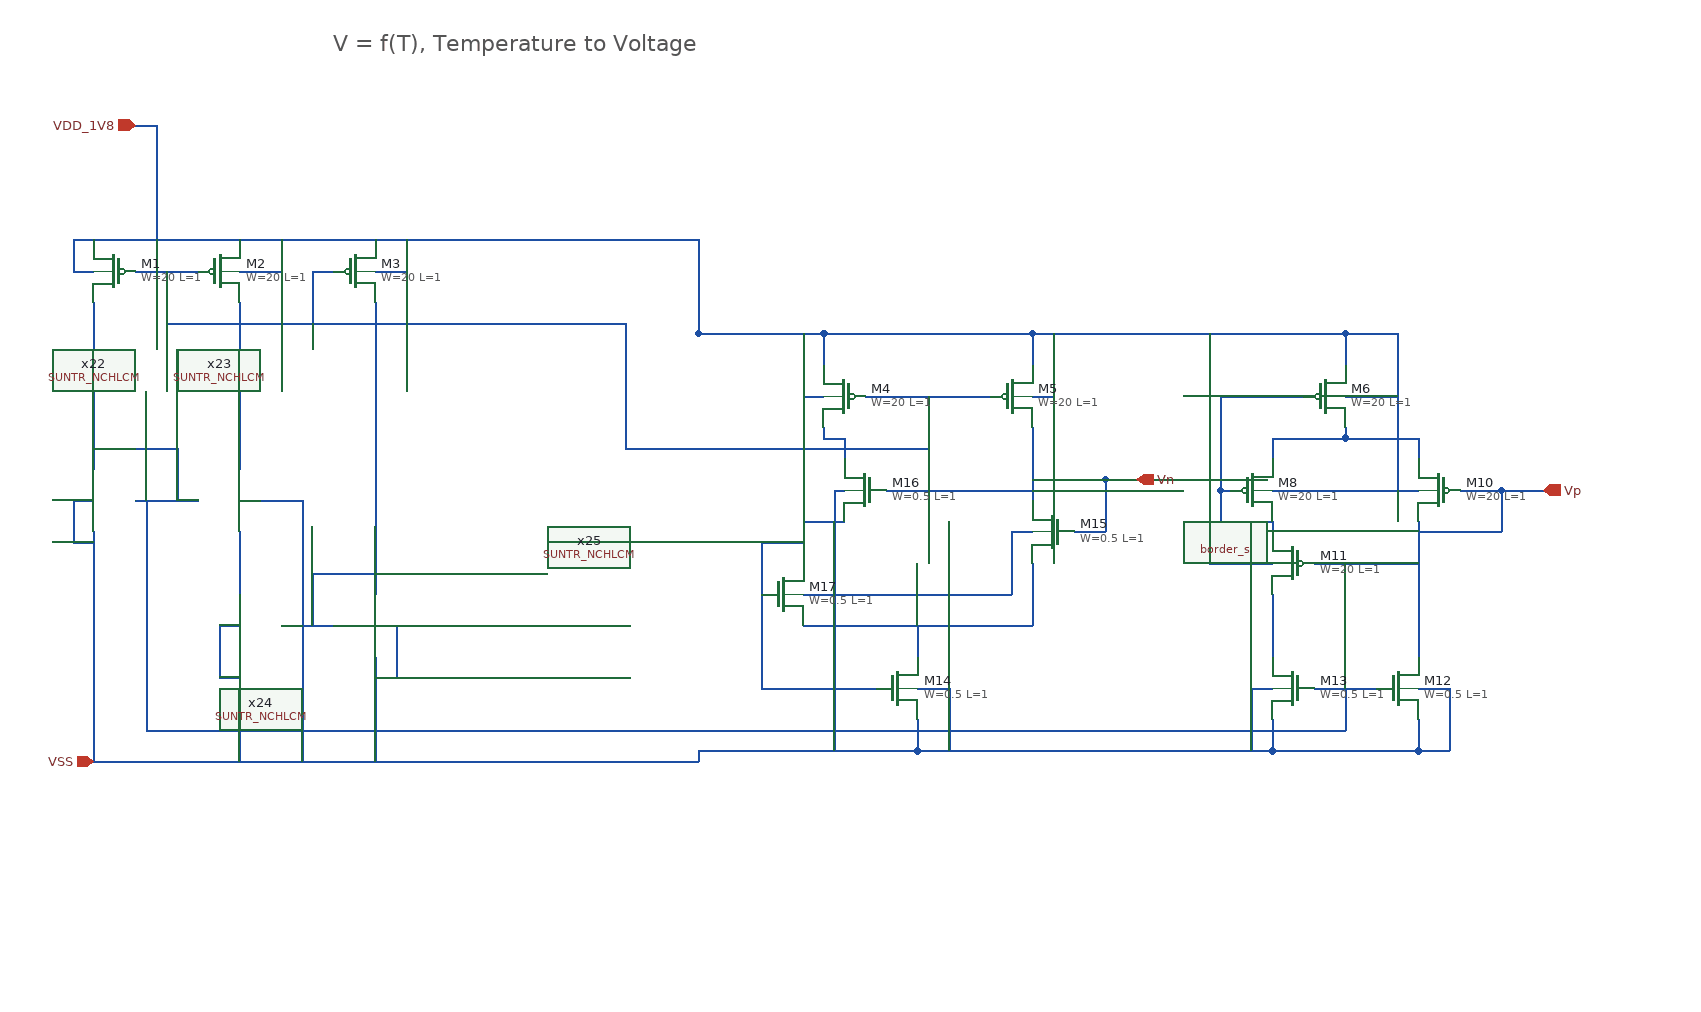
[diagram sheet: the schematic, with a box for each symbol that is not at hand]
v {xschem version=3.4.4 file_version=1.2
}
G {}
K {}
V {}
S {}
E {}
T {V = f(T), Temperature to Voltage} 400 -1040 0 0 1 1 {}
N 1070 -660 1070 -590 {
lab=Vn}
N 870 -750 870 -720 {
lab=VDD_1V8}
N 750 -750 870 -750 {
lab=VDD_1V8}
N 750 -750 870 -750 {
lab=VDD_1V8}
N 870 -750 1070 -750 {
lab=VDD_1V8}
N 1070 -750 1070 -720 {
lab=VDD_1V8}
N 1070 -610 1140 -610 {
lab=Vn}
N 1140 -610 1140 -560 {
lab=Vn}
N 1110 -560 1140 -560 {
lab=Vn}
N 1140 -610 1170 -610 {
lab=Vn}
N 1440 -570 1440 -440 {
lab=Vp}
N 1440 -650 1440 -630 {
lab=#net1}
N 1370 -650 1440 -650 {
lab=#net1}
N 1370 -660 1370 -650 {
lab=#net1}
N 1300 -650 1370 -650 {
lab=#net1}
N 1300 -650 1300 -630 {
lab=#net1}
N 1300 -570 1300 -560 {
lab=#net2}
N 1340 -530 1440 -530 {
lab=Vp}
N 1340 -410 1400 -410 {
lab=#net3}
N 1370 -750 1370 -720 {
lab=VDD_1V8}
N 1070 -750 1370 -750 {
lab=VDD_1V8}
N 1250 -690 1330 -690 {
lab=#net2}
N 1250 -690 1250 -600 {
lab=#net2}
N 1250 -600 1260 -600 {
lab=#net2}
N 1250 -600 1250 -570 {
lab=#net2}
N 1250 -570 1300 -570 {
lab=#net2}
N 1480 -600 1520 -600 {
lab=Vp}
N 1520 -600 1520 -560 {
lab=Vp}
N 1440 -560 1520 -560 {
lab=Vp}
N 1520 -600 1560 -600 {
lab=Vp}
N 1440 -380 1440 -350 {
lab=VSS}
N 1300 -350 1440 -350 {
lab=VSS}
N 1300 -380 1300 -350 {
lab=VSS}
N 960 -350 1300 -350 {
lab=VSS}
N 960 -380 960 -350 {
lab=VSS}
N 750 -350 960 -350 {
lab=VSS}
N 970 -690 970 -640 {
lab=#net4}
N 910 -690 1030 -690 {
lab=#net4}
N 1300 -500 1300 -440 {
lab=#net5}
N 890 -650 890 -630 {
lab=#net6}
N 870 -650 890 -650 {
lab=#net6}
N 870 -660 870 -650 {
lab=#net6}
N 930 -600 1070 -600 {
lab=Vn}
N 850 -690 870 -690 {
lab=VDD_1V8}
N 850 -750 850 -690 {
lab=VDD_1V8}
N 1070 -690 1090 -690 {
lab=VDD_1V8}
N 1090 -750 1090 -690 {
lab=VDD_1V8}
N 1240 -530 1300 -530 {
lab=VDD_1V8}
N 1240 -750 1240 -530 {
lab=VDD_1V8}
N 1300 -600 1440 -600 {
lab=VDD_1V8}
N 1420 -750 1420 -600 {
lab=VDD_1V8}
N 1370 -750 1420 -750 {
lab=VDD_1V8}
N 1370 -690 1420 -690 {
lab=VDD_1V8}
N 880 -600 890 -600 {
lab=VSS}
N 880 -600 880 -350 {
lab=VSS}
N 850 -470 1070 -470 {
lab=#net7}
N 960 -470 960 -440 {
lab=#net7}
N 850 -570 890 -570 {
lab=#net8}
N 850 -570 850 -530 {
lab=#net8}
N 810 -550 810 -500 {
lab=#net8}
N 810 -550 850 -550 {
lab=#net8}
N 810 -500 810 -410 {
lab=#net8}
N 810 -410 920 -410 {
lab=#net8}
N 850 -500 880 -500 {
lab=VSS}
N 1050 -560 1070 -560 {
lab=VSS}
N 1050 -560 1050 -500 {
lab=VSS}
N 880 -500 1050 -500 {
lab=VSS}
N 960 -410 990 -410 {
lab=VSS}
N 990 -410 990 -350 {
lab=VSS}
N 1280 -410 1300 -410 {
lab=VSS}
N 1280 -410 1280 -350 {
lab=VSS}
N 1440 -410 1470 -410 {
lab=VSS}
N 1470 -410 1470 -350 {
lab=VSS}
N 1440 -350 1470 -350 {
lab=VSS}
N 210 -810 270 -810 {
lab=#net4}
N 380 -810 400 -810 {
lab=#net4}
N 210 -590 270 -590 {
lab=#net3}
N 250 -630 250 -590 {
lab=#net3}
N 170 -640 250 -640 {
lab=#net3}
N 250 -640 250 -630 {
lab=#net3}
N 170 -560 170 -340 {
lab=VSS}
N 170 -340 570 -340 {
lab=VSS}
N 310 -560 310 -500 {
lab=#net9}
N 350 -470 400 -470 {
lab=#net10}
N 310 -440 310 -340 {
lab=VSS}
N 310 -840 330 -840 {
lab=VDD_1V8}
N 170 -840 310 -840 {
lab=VDD_1V8}
N 330 -840 440 -840 {
lab=VDD_1V8}
N 440 -840 560 -840 {
lab=VDD_1V8}
N 560 -840 750 -840 {
lab=VDD_1V8}
N 750 -840 750 -750 {
lab=VDD_1V8}
N 570 -340 750 -340 {
lab=VSS}
N 750 -350 750 -340 {
lab=VSS}
N 1370 -410 1370 -370 {
lab=#net3}
N 220 -370 1370 -370 {
lab=#net3}
N 220 -590 220 -370 {
lab=#net3}
N 310 -590 370 -590 {
lab=VSS}
N 370 -590 370 -340 {
lab=VSS}
N 310 -810 350 -810 {
lab=VDD_1V8}
N 350 -840 350 -810 {
lab=VDD_1V8}
N 440 -810 470 -810 {
lab=VDD_1V8}
N 470 -840 470 -810 {
lab=VDD_1V8}
N 440 -440 440 -340 {
lab=VSS}
N 380 -520 380 -470 {
lab=#net10}
N 380 -520 440 -520 {
lab=#net10}
N 150 -840 170 -840 {
lab=VDD_1V8}
N 150 -810 170 -810 {
lab=VDD_1V8}
N 150 -590 170 -590 {
lab=VSS}
N 150 -590 150 -550 {
lab=VSS}
N 150 -550 170 -550 {
lab=VSS}
N 230 -950 230 -840 {
lab=VDD_1V8}
N 210 -950 230 -950 {
lab=VDD_1V8}
N 170 -780 170 -620 {
lab=#net3}
N 310 -780 310 -620 {
lab=#net11}
N 440 -780 440 -500 {
lab=#net10}
N 240 -810 240 -760 {
lab=#net4}
N 240 -760 680 -760 {
lab=#net4}
N 680 -760 680 -640 {
lab=#net4}
N 680 -640 970 -640 {
lab=#net4}
N 380 -810 380 -760 {
lab=#net4}
N 150 -840 150 -810 {
lab=VDD_1V8}
N 290 -470 310 -470 {
lab=VSS}
N 290 -470 290 -420 {
lab=VSS}
N 290 -420 310 -420 {
lab=VSS}
N 440 -470 460 -470 {
lab=VSS}
N 460 -470 460 -420 {
lab=VSS}
N 440 -420 460 -420 {
lab=VSS}
N 1070 -530 1070 -470 {
lab=#net7}
C {cborder/border_s.sym} 1250 -170 0 0 {
user="GR06"
company="GR06"}
C {devices/ipin.sym} 210 -950 0 0 {name=p1 lab=VDD_1V8
}
C {devices/ipin.sym} 170 -340 0 0 {name=p3 lab=VSS}
C {devices/opin.sym} 1170 -610 0 0 {name=p4 lab=Vn}
C {devices/opin.sym} 1560 -600 0 0 {name=p5 lab=Vp}
C {SUN_TR_SKY130NM/SUNTR_NCHLCM.sym} 210 -590 0 1 {name=x22 }
C {SUN_TR_SKY130NM/SUNTR_NCHLCM.sym} 270 -590 0 0 {name=x23 }
C {SUN_TR_SKY130NM/SUNTR_NCHLCM.sym} 350 -470 0 1 {name=x24 }
C {SUN_TR_SKY130NM/SUNTR_NCHLCM.sym} 400 -470 0 0 {name=x25 }
C {sky130_fd_pr/pfet_01v8.sym} 190 -810 0 1 {name=M1
L=1
W=20
nf=1
mult=1
ad="'int((nf+1)/2) * W/nf * 0.29'"
pd="'2*int((nf+1)/2) * (W/nf + 0.29)'"
as="'int((nf+2)/2) * W/nf * 0.29'"
ps="'2*int((nf+2)/2) * (W/nf + 0.29)'"
nrd="'0.29 / W'" nrs="'0.29 / W'"
sa=0 sb=0 sd=0
model=pfet_01v8
spiceprefix=X
}
C {sky130_fd_pr/pfet_01v8.sym} 290 -810 0 0 {name=M2
L=1
W=20
nf=1
mult=1
ad="'int((nf+1)/2) * W/nf * 0.29'"
pd="'2*int((nf+1)/2) * (W/nf + 0.29)'"
as="'int((nf+2)/2) * W/nf * 0.29'"
ps="'2*int((nf+2)/2) * (W/nf + 0.29)'"
nrd="'0.29 / W'" nrs="'0.29 / W'"
sa=0 sb=0 sd=0
model=pfet_01v8
spiceprefix=X
}
C {sky130_fd_pr/pfet_01v8.sym} 420 -810 0 0 {name=M3
L=1
W=20
nf=1
mult=1
ad="'int((nf+1)/2) * W/nf * 0.29'"
pd="'2*int((nf+1)/2) * (W/nf + 0.29)'"
as="'int((nf+2)/2) * W/nf * 0.29'"
ps="'2*int((nf+2)/2) * (W/nf + 0.29)'"
nrd="'0.29 / W'" nrs="'0.29 / W'"
sa=0 sb=0 sd=0
model=pfet_01v8
spiceprefix=X
}
C {sky130_fd_pr/pfet_01v8.sym} 890 -690 0 1 {name=M4
L=1
W=20
nf=1
mult=1
ad="'int((nf+1)/2) * W/nf * 0.29'"
pd="'2*int((nf+1)/2) * (W/nf + 0.29)'"
as="'int((nf+2)/2) * W/nf * 0.29'"
ps="'2*int((nf+2)/2) * (W/nf + 0.29)'"
nrd="'0.29 / W'" nrs="'0.29 / W'"
sa=0 sb=0 sd=0
model=pfet_01v8
spiceprefix=X
}
C {sky130_fd_pr/pfet_01v8.sym} 1050 -690 0 0 {name=M5
L=1
W=20
nf=1
mult=1
ad="'int((nf+1)/2) * W/nf * 0.29'"
pd="'2*int((nf+1)/2) * (W/nf + 0.29)'"
as="'int((nf+2)/2) * W/nf * 0.29'"
ps="'2*int((nf+2)/2) * (W/nf + 0.29)'"
nrd="'0.29 / W'" nrs="'0.29 / W'"
sa=0 sb=0 sd=0
model=pfet_01v8
spiceprefix=X
}
C {sky130_fd_pr/pfet_01v8.sym} 1350 -690 0 0 {name=M6
L=1
W=20
nf=1
mult=1
ad="'int((nf+1)/2) * W/nf * 0.29'"
pd="'2*int((nf+1)/2) * (W/nf + 0.29)'"
as="'int((nf+2)/2) * W/nf * 0.29'"
ps="'2*int((nf+2)/2) * (W/nf + 0.29)'"
nrd="'0.29 / W'" nrs="'0.29 / W'"
sa=0 sb=0 sd=0
model=pfet_01v8
spiceprefix=X
}
C {sky130_fd_pr/pfet_01v8.sym} 1280 -600 0 0 {name=M8
L=1
W=20
nf=1
mult=1
ad="'int((nf+1)/2) * W/nf * 0.29'"
pd="'2*int((nf+1)/2) * (W/nf + 0.29)'"
as="'int((nf+2)/2) * W/nf * 0.29'"
ps="'2*int((nf+2)/2) * (W/nf + 0.29)'"
nrd="'0.29 / W'" nrs="'0.29 / W'"
sa=0 sb=0 sd=0
model=pfet_01v8
spiceprefix=X
}
C {sky130_fd_pr/pfet_01v8.sym} 1460 -600 0 1 {name=M10
L=1
W=20
nf=1
mult=1
ad="'int((nf+1)/2) * W/nf * 0.29'"
pd="'2*int((nf+1)/2) * (W/nf + 0.29)'"
as="'int((nf+2)/2) * W/nf * 0.29'"
ps="'2*int((nf+2)/2) * (W/nf + 0.29)'"
nrd="'0.29 / W'" nrs="'0.29 / W'"
sa=0 sb=0 sd=0
model=pfet_01v8
spiceprefix=X
}
C {sky130_fd_pr/pfet_01v8.sym} 1320 -530 0 1 {name=M11
L=1
W=20
nf=1
mult=1
ad="'int((nf+1)/2) * W/nf * 0.29'"
pd="'2*int((nf+1)/2) * (W/nf + 0.29)'"
as="'int((nf+2)/2) * W/nf * 0.29'"
ps="'2*int((nf+2)/2) * (W/nf + 0.29)'"
nrd="'0.29 / W'" nrs="'0.29 / W'"
sa=0 sb=0 sd=0
model=pfet_01v8
spiceprefix=X
}
C {sky130_fd_pr/nfet_01v8.sym} 1420 -410 2 1 {name=M12
L=1
W=0.5
nf=1
mult=1
ad="'int((nf+1)/2) * W/nf * 0.29'"
pd="'2*int((nf+1)/2) * (W/nf + 0.29)'"
as="'int((nf+2)/2) * W/nf * 0.29'"
ps="'2*int((nf+2)/2) * (W/nf + 0.29)'"
nrd="'0.29 / W'" nrs="'0.29 / W'"
sa=0 sb=0 sd=0
model=nfet_01v8
spiceprefix=X
}
C {sky130_fd_pr/nfet_01v8.sym} 1320 -410 2 0 {name=M13
L=1
W=0.5
nf=1
mult=1
ad="'int((nf+1)/2) * W/nf * 0.29'"
pd="'2*int((nf+1)/2) * (W/nf + 0.29)'"
as="'int((nf+2)/2) * W/nf * 0.29'"
ps="'2*int((nf+2)/2) * (W/nf + 0.29)'"
nrd="'0.29 / W'" nrs="'0.29 / W'"
sa=0 sb=0 sd=0
model=nfet_01v8
spiceprefix=X
}
C {sky130_fd_pr/nfet_01v8.sym} 940 -410 2 1 {name=M14
L=1
W=0.5
nf=1
mult=1
ad="'int((nf+1)/2) * W/nf * 0.29'"
pd="'2*int((nf+1)/2) * (W/nf + 0.29)'"
as="'int((nf+2)/2) * W/nf * 0.29'"
ps="'2*int((nf+2)/2) * (W/nf + 0.29)'"
nrd="'0.29 / W'" nrs="'0.29 / W'"
sa=0 sb=0 sd=0
model=nfet_01v8
spiceprefix=X
}
C {sky130_fd_pr/nfet_01v8.sym} 1090 -560 2 0 {name=M15
L=1
W=0.5
nf=1
mult=1
ad="'int((nf+1)/2) * W/nf * 0.29'"
pd="'2*int((nf+1)/2) * (W/nf + 0.29)'"
as="'int((nf+2)/2) * W/nf * 0.29'"
ps="'2*int((nf+2)/2) * (W/nf + 0.29)'"
nrd="'0.29 / W'" nrs="'0.29 / W'"
sa=0 sb=0 sd=0
model=nfet_01v8
spiceprefix=X
}
C {sky130_fd_pr/nfet_01v8.sym} 910 -600 2 0 {name=M16
L=1
W=0.5
nf=1
mult=1
ad="'int((nf+1)/2) * W/nf * 0.29'"
pd="'2*int((nf+1)/2) * (W/nf + 0.29)'"
as="'int((nf+2)/2) * W/nf * 0.29'"
ps="'2*int((nf+2)/2) * (W/nf + 0.29)'"
nrd="'0.29 / W'" nrs="'0.29 / W'"
sa=0 sb=0 sd=0
model=nfet_01v8
spiceprefix=X
}
C {sky130_fd_pr/nfet_01v8.sym} 830 -500 2 1 {name=M17
L=1
W=0.5
nf=1
mult=1
ad="'int((nf+1)/2) * W/nf * 0.29'"
pd="'2*int((nf+1)/2) * (W/nf + 0.29)'"
as="'int((nf+2)/2) * W/nf * 0.29'"
ps="'2*int((nf+2)/2) * (W/nf + 0.29)'"
nrd="'0.29 / W'" nrs="'0.29 / W'"
sa=0 sb=0 sd=0
model=nfet_01v8
spiceprefix=X
}
